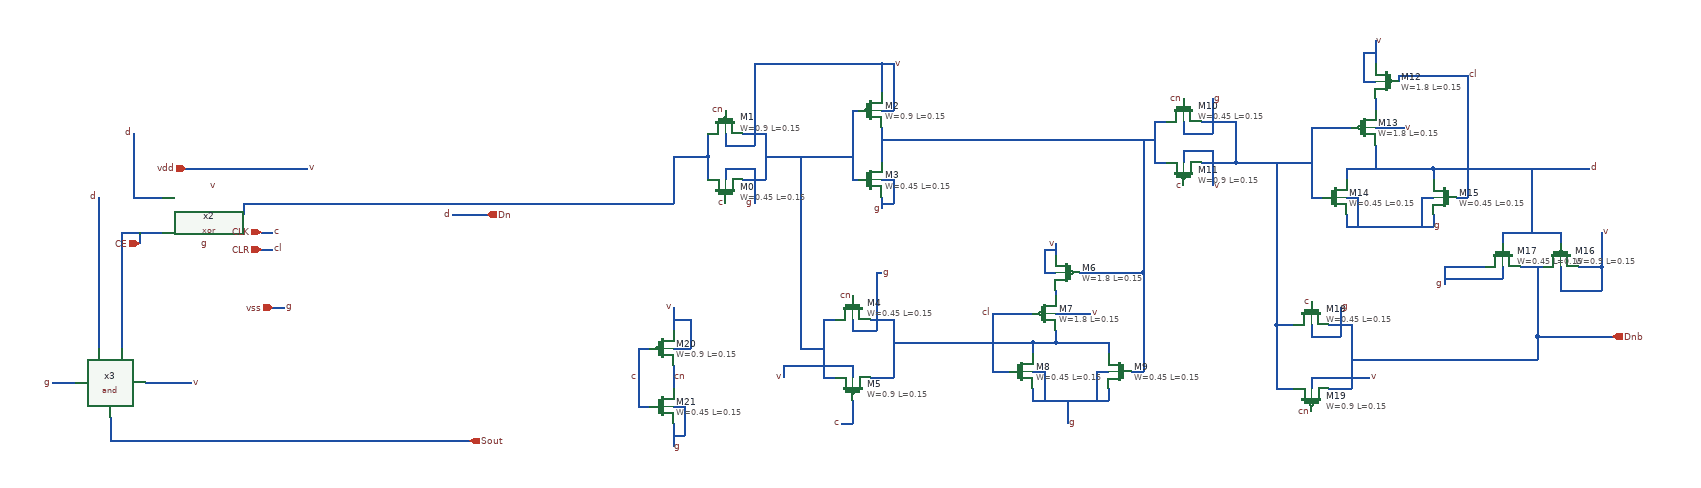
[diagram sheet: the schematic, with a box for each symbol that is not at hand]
v {xschem version=2.9.9 file_version=1.2 }
G {}
K {}
V {}
S {}
E {}
N 60 -30 60 230 { lab=d}
N 120 -30 170 -30 { lab=d}
N 120 -140 120 -30 { lab=d}
N 140 290 190 290 { lab=v}
N -20 290 20 290 { lab=g}
N 80 350 80 390 { lab=Sout}
N 80 390 700 390 { lab=Sout}
N 670 0 730 -0 { lab=d}
N 210 -80 230 -80 { lab=vdd}
N 360 160 380 160 { lab=g}
N 340 30 360 30 { lab=c}
N 340 60 360 60 { lab=cl}
N 130 30 130 50 { lab=CE}
N 240 -80 420 -80 { lab=v}
N 230 -80 240 -80 { lab=vdd}
N 190 290 220 290 { lab=v}
N 100 30 100 230 { lab=CE}
N 100 30 170 30 { lab=CE}
N 310 -20 310 -0 { lab=#net1}
N 310 -20 360 -20 { lab=#net1}
N 1050 -100 1110 -100 { lab=#net1}
N 1110 -140 1110 -100 { lab=#net1}
N 1110 -100 1110 -60 { lab=#net1}
N 1170 -140 1210 -140 { lab=#net2}
N 1170 -60 1210 -60 { lab=#net2}
N 1210 -140 1210 -60 { lab=#net2}
N 1210 -100 1290 -100 { lab=#net2}
N 1360 -60 1370 -60 { lab=#net2}
N 1360 -180 1360 -60 { lab=#net2}
N 1360 -180 1370 -180 { lab=#net2}
N 1410 -150 1410 -90 { lab=#net3}
N 1290 -100 1360 -100 { lab=#net2}
N 1140 -140 1140 -120 { lab=v}
N 1140 -120 1190 -120 { lab=v}
N 1190 -260 1190 -120 { lab=v}
N 1410 -260 1410 -210 { lab=v}
N 1190 -260 1410 -260 { lab=v}
N 1390 280 1410 280 { lab=#net4}
N 1390 180 1410 180 { lab=#net4}
N 1310 280 1330 280 { lab=#net2}
N 1310 180 1310 280 { lab=#net2}
N 1310 180 1330 180 { lab=#net2}
N 1270 230 1310 230 { lab=#net2}
N 1270 -100 1270 230 { lab=#net2}
N 1360 180 1360 200 { lab=g}
N 1360 200 1400 200 { lab=g}
N 1400 100 1400 200 { lab=g}
N 1400 100 1410 100 { lab=g}
N 1360 320 1360 360 { lab=c}
N 1340 360 1360 360 { lab=c}
N 1360 260 1360 280 { lab=v}
N 1240 260 1360 260 { lab=v}
N 1240 260 1240 280 { lab=v}
N 1140 -80 1140 -60 { lab=g}
N 1140 -80 1190 -80 { lab=g}
N 1190 -80 1190 -40 { lab=g}
N 1190 -40 1190 -20 { lab=g}
N 1410 280 1430 280 { lab=#net4}
N 1430 180 1430 280 { lab=#net4}
N 1410 180 1430 180 { lab=#net4}
N 1600 270 1630 270 { lab=cl}
N 1600 170 1600 270 { lab=cl}
N 1600 170 1670 170 { lab=cl}
N 1710 130 1710 140 { lab=#net5}
N 1710 200 1710 220 { lab=#net4}
N 1670 220 1710 220 { lab=#net4}
N 1670 220 1670 240 { lab=#net4}
N 1710 220 1800 220 { lab=#net4}
N 1800 220 1800 240 { lab=#net4}
N 1670 300 1670 320 { lab=g}
N 1670 320 1800 320 { lab=g}
N 1800 300 1800 320 { lab=g}
N 1730 320 1730 360 { lab=g}
N 1840 270 1860 270 { lab=#net3}
N 1860 100 1860 270 { lab=#net3}
N 1750 100 1860 100 { lab=#net3}
N 1710 50 1710 70 { lab=v}
N 1430 220 1670 220 { lab=#net4}
N 1670 270 1690 270 { lab=g}
N 1690 270 1690 320 { lab=g}
N 1780 270 1800 270 { lab=g}
N 1780 270 1780 320 { lab=g}
N 1710 170 1770 170 { lab=v}
N 1690 100 1710 100 { lab=v}
N 1690 60 1690 100 { lab=v}
N 1690 60 1710 60 { lab=v}
N 1410 -30 1410 -10 { lab=g}
N 1410 -20 1430 -20 { lab=g}
N 1430 -60 1430 -20 { lab=g}
N 1410 -60 1430 -60 { lab=g}
N 1410 -180 1430 -180 { lab=v}
N 1430 -260 1430 -180 { lab=v}
N 1410 -260 1430 -260 { lab=v}
N 1880 -160 1900 -160 { lab=#net3}
N 1880 -160 1880 -90 { lab=#net3}
N 1880 -90 1900 -90 { lab=#net3}
N 1410 -130 1880 -130 { lab=#net3}
N 1860 -130 1860 100 { lab=#net3}
N 1960 -90 2020 -90 { lab=#net6}
N 2020 -160 2020 -90 { lab=#net6}
N 1960 -160 2020 -160 { lab=#net6}
N 1930 -160 1930 -140 { lab=g}
N 1930 -140 1980 -140 { lab=g}
N 1980 -200 1980 -140 { lab=g}
N 1930 -110 1930 -90 { lab=v}
N 1930 -110 1980 -110 { lab=v}
N 1980 -110 1980 -50 { lab=v}
N 2210 -80 2210 -60 { lab=d}
N 2210 -80 2360 -80 { lab=d}
N 2360 -80 2360 -60 { lab=d}
N 2260 -120 2260 -80 { lab=d}
N 2260 -200 2260 -180 { lab=#net7}
N 2260 -300 2260 -260 { lab=v}
N 2210 0 2210 20 { lab=g}
N 2210 20 2360 20 { lab=g}
N 2360 0 2360 20 { lab=g}
N 2150 -30 2170 -30 { lab=#net6}
N 2150 -150 2150 -30 { lab=#net6}
N 2150 -150 2220 -150 { lab=#net6}
N 2400 -30 2420 -30 { lab=cl}
N 2420 -240 2420 -30 { lab=cl}
N 2300 -240 2420 -240 { lab=cl}
N 2300 -240 2300 -230 { lab=cl}
N 2020 -90 2150 -90 { lab=#net6}
N 2360 -80 2630 -80 { lab=d}
N 2240 -230 2260 -230 { lab=v}
N 2240 -280 2240 -230 { lab=v}
N 2240 -280 2260 -280 { lab=v}
N 2260 -150 2310 -150 { lab=v}
N 2210 -30 2230 -30 { lab=g}
N 2230 -20 2230 20 { lab=g}
N 2230 -30 2230 -20 { lab=g}
N 2340 -30 2360 -30 { lab=g}
N 2340 -30 2340 20 { lab=g}
N 2480 30 2480 50 { lab=d}
N 2480 30 2580 30 { lab=d}
N 2580 30 2580 50 { lab=d}
N 2530 -80 2530 30 { lab=d}
N 2380 90 2450 90 { lab=g}
N 2380 90 2380 120 { lab=g}
N 2610 90 2650 90 { lab=v}
N 2650 30 2650 90 { lab=v}
N 2510 90 2550 90 { lab=Dnb}
N 2540 90 2540 210 { lab=Dnb}
N 2540 210 2670 210 { lab=Dnb}
N 2580 90 2580 130 { lab=v}
N 2580 130 2650 130 { lab=v}
N 2650 90 2650 130 { lab=v}
N 2480 90 2480 110 { lab=g}
N 2380 110 2480 110 { lab=g}
N 2180 190 2220 190 { lab=Dnb}
N 2220 190 2220 300 { lab=Dnb}
N 2180 300 2220 300 { lab=Dnb}
N 2220 250 2540 250 { lab=Dnb}
N 2540 210 2540 250 { lab=Dnb}
N 2090 190 2120 190 { lab=#net6}
N 2090 190 2090 300 { lab=#net6}
N 2090 300 2120 300 { lab=#net6}
N 2090 -90 2090 190 { lab=#net6}
N 2150 190 2150 210 { lab=g}
N 2150 210 2200 210 { lab=g}
N 2200 160 2200 210 { lab=g}
N 2150 280 2150 300 { lab=v}
N 2150 280 2250 280 { lab=v}
N 1050 260 1050 300 { lab=cn}
N 990 330 1010 330 { lab=c}
N 990 230 990 330 { lab=c}
N 990 230 1010 230 { lab=c}
N 1050 160 1050 200 { lab=v}
N 1050 360 1050 400 { lab=g}
N 1050 330 1070 330 { lab=g}
N 1070 330 1070 380 { lab=g}
N 1050 380 1070 380 { lab=g}
N 1050 230 1080 230 { lab=v}
N 1080 180 1080 230 { lab=v}
N 1050 180 1080 180 { lab=v}
N 360 -20 1050 -20 { lab=#net1}
N 1050 -100 1050 -20 { lab=#net1}
C {xor/xor.sym} 180 0 0 0 {name=x2}
C {and/and.sym} 80 270 1 0 {name=x3}
C {opin.sym} 730 0 0 0 {name=p1 lab=Dn}
C {opin.sym} 700 390 0 0 {name=p2 lab=Sout}
C {ipin.sym} 210 -80 0 0 {name=p3 lab=vdd}
C {ipin.sym} 360 160 0 0 {name=p4 lab=vss}
C {ipin.sym} 340 30 0 0 {name=p5 lab=CLK}
C {ipin.sym} 340 60 0 0 {name=p6 lab=CLR}
C {ipin.sym} 130 50 3 0 {name=p7 lab=CE}
C {sky130_fd_pr/nfet_01v8.sym} 1140 -40 1 1 {name=M0
L=0.15
W=0.45
nf=1 
mult=1
ad="'int((nf+1)/2) * W/nf * 0.29'" 
pd="'2*int((nf+1)/2) * (W/nf + 0.29)'"
as="'int((nf+2)/2) * W/nf * 0.29'" 
ps="'2*int((nf+2)/2) * (W/nf + 0.29)'"
nrd="'0.29 / W'" nrs="'0.29 / W'"
sa=0 sb=0 sd=0
model=nfet_01v8
spiceprefix=X
}
C {sky130_fd_pr/pfet_01v8.sym} 1140 -160 1 0 {name=M1
L=0.15
W=0.9
nf=1
mult=1
ad="'int((nf+1)/2) * W/nf * 0.29'" 
pd="'2*int((nf+1)/2) * (W/nf + 0.29)'"
as="'int((nf+2)/2) * W/nf * 0.29'" 
ps="'2*int((nf+2)/2) * (W/nf + 0.29)'"
nrd="'0.29 / W'" nrs="'0.29 / W'"
sa=0 sb=0 sd=0
model=pfet_01v8
spiceprefix=X
}
C {sky130_fd_pr/pfet_01v8.sym} 1390 -180 0 0 {name=M2
L=0.15
W=0.9
nf=1
mult=1
ad="'int((nf+1)/2) * W/nf * 0.29'" 
pd="'2*int((nf+1)/2) * (W/nf + 0.29)'"
as="'int((nf+2)/2) * W/nf * 0.29'" 
ps="'2*int((nf+2)/2) * (W/nf + 0.29)'"
nrd="'0.29 / W'" nrs="'0.29 / W'"
sa=0 sb=0 sd=0
model=pfet_01v8
spiceprefix=X
}
C {sky130_fd_pr/nfet_01v8.sym} 1390 -60 0 0 {name=M3
L=0.15
W=0.45
nf=1 
mult=1
ad="'int((nf+1)/2) * W/nf * 0.29'" 
pd="'2*int((nf+1)/2) * (W/nf + 0.29)'"
as="'int((nf+2)/2) * W/nf * 0.29'" 
ps="'2*int((nf+2)/2) * (W/nf + 0.29)'"
nrd="'0.29 / W'" nrs="'0.29 / W'"
sa=0 sb=0 sd=0
model=nfet_01v8
spiceprefix=X
}
C {sky130_fd_pr/nfet_01v8.sym} 1360 160 3 1 {name=M4
L=0.15
W=0.45
nf=1 
mult=1
ad="'int((nf+1)/2) * W/nf * 0.29'" 
pd="'2*int((nf+1)/2) * (W/nf + 0.29)'"
as="'int((nf+2)/2) * W/nf * 0.29'" 
ps="'2*int((nf+2)/2) * (W/nf + 0.29)'"
nrd="'0.29 / W'" nrs="'0.29 / W'"
sa=0 sb=0 sd=0
model=nfet_01v8
spiceprefix=X
}
C {sky130_fd_pr/pfet_01v8.sym} 1360 300 3 0 {name=M5
L=0.15
W=0.9
nf=1
mult=1
ad="'int((nf+1)/2) * W/nf * 0.29'" 
pd="'2*int((nf+1)/2) * (W/nf + 0.29)'"
as="'int((nf+2)/2) * W/nf * 0.29'" 
ps="'2*int((nf+2)/2) * (W/nf + 0.29)'"
nrd="'0.29 / W'" nrs="'0.29 / W'"
sa=0 sb=0 sd=0
model=pfet_01v8
spiceprefix=X
}
C {sky130_fd_pr/pfet_01v8.sym} 1730 100 0 1 {name=M6
L=0.15
W=1.8
nf=1
mult=1
ad="'int((nf+1)/2) * W/nf * 0.29'" 
pd="'2*int((nf+1)/2) * (W/nf + 0.29)'"
as="'int((nf+2)/2) * W/nf * 0.29'" 
ps="'2*int((nf+2)/2) * (W/nf + 0.29)'"
nrd="'0.29 / W'" nrs="'0.29 / W'"
sa=0 sb=0 sd=0
model=pfet_01v8
spiceprefix=X
}
C {sky130_fd_pr/pfet_01v8.sym} 1690 170 0 0 {name=M7
L=0.15
W=1.8
nf=1
mult=1
ad="'int((nf+1)/2) * W/nf * 0.29'" 
pd="'2*int((nf+1)/2) * (W/nf + 0.29)'"
as="'int((nf+2)/2) * W/nf * 0.29'" 
ps="'2*int((nf+2)/2) * (W/nf + 0.29)'"
nrd="'0.29 / W'" nrs="'0.29 / W'"
sa=0 sb=0 sd=0
model=pfet_01v8
spiceprefix=X
}
C {sky130_fd_pr/nfet_01v8.sym} 1650 270 0 0 {name=M8
L=0.15
W=0.45
nf=1 
mult=1
ad="'int((nf+1)/2) * W/nf * 0.29'" 
pd="'2*int((nf+1)/2) * (W/nf + 0.29)'"
as="'int((nf+2)/2) * W/nf * 0.29'" 
ps="'2*int((nf+2)/2) * (W/nf + 0.29)'"
nrd="'0.29 / W'" nrs="'0.29 / W'"
sa=0 sb=0 sd=0
model=nfet_01v8
spiceprefix=X
}
C {sky130_fd_pr/nfet_01v8.sym} 1820 270 0 1 {name=M9
L=0.15
W=0.45
nf=1 
mult=1
ad="'int((nf+1)/2) * W/nf * 0.29'" 
pd="'2*int((nf+1)/2) * (W/nf + 0.29)'"
as="'int((nf+2)/2) * W/nf * 0.29'" 
ps="'2*int((nf+2)/2) * (W/nf + 0.29)'"
nrd="'0.29 / W'" nrs="'0.29 / W'"
sa=0 sb=0 sd=0
model=nfet_01v8
spiceprefix=X
}
C {sky130_fd_pr/nfet_01v8.sym} 1930 -180 1 0 {name=M10
L=0.15
W=0.45
nf=1 
mult=1
ad="'int((nf+1)/2) * W/nf * 0.29'" 
pd="'2*int((nf+1)/2) * (W/nf + 0.29)'"
as="'int((nf+2)/2) * W/nf * 0.29'" 
ps="'2*int((nf+2)/2) * (W/nf + 0.29)'"
nrd="'0.29 / W'" nrs="'0.29 / W'"
sa=0 sb=0 sd=0
model=nfet_01v8
spiceprefix=X
}
C {sky130_fd_pr/pfet_01v8.sym} 1930 -70 1 1 {name=M11
L=0.15
W=0.9
nf=1
mult=1
ad="'int((nf+1)/2) * W/nf * 0.29'" 
pd="'2*int((nf+1)/2) * (W/nf + 0.29)'"
as="'int((nf+2)/2) * W/nf * 0.29'" 
ps="'2*int((nf+2)/2) * (W/nf + 0.29)'"
nrd="'0.29 / W'" nrs="'0.29 / W'"
sa=0 sb=0 sd=0
model=pfet_01v8
spiceprefix=X
}
C {sky130_fd_pr/pfet_01v8.sym} 2280 -230 0 1 {name=M12
L=0.15
W=1.8
nf=1
mult=1
ad="'int((nf+1)/2) * W/nf * 0.29'" 
pd="'2*int((nf+1)/2) * (W/nf + 0.29)'"
as="'int((nf+2)/2) * W/nf * 0.29'" 
ps="'2*int((nf+2)/2) * (W/nf + 0.29)'"
nrd="'0.29 / W'" nrs="'0.29 / W'"
sa=0 sb=0 sd=0
model=pfet_01v8
spiceprefix=X
}
C {sky130_fd_pr/pfet_01v8.sym} 2240 -150 0 0 {name=M13
L=0.15
W=1.8
nf=1
mult=1
ad="'int((nf+1)/2) * W/nf * 0.29'" 
pd="'2*int((nf+1)/2) * (W/nf + 0.29)'"
as="'int((nf+2)/2) * W/nf * 0.29'" 
ps="'2*int((nf+2)/2) * (W/nf + 0.29)'"
nrd="'0.29 / W'" nrs="'0.29 / W'"
sa=0 sb=0 sd=0
model=pfet_01v8
spiceprefix=X
}
C {sky130_fd_pr/nfet_01v8.sym} 2190 -30 0 0 {name=M14
L=0.15
W=0.45
nf=1 
mult=1
ad="'int((nf+1)/2) * W/nf * 0.29'" 
pd="'2*int((nf+1)/2) * (W/nf + 0.29)'"
as="'int((nf+2)/2) * W/nf * 0.29'" 
ps="'2*int((nf+2)/2) * (W/nf + 0.29)'"
nrd="'0.29 / W'" nrs="'0.29 / W'"
sa=0 sb=0 sd=0
model=nfet_01v8
spiceprefix=X
}
C {sky130_fd_pr/nfet_01v8.sym} 2380 -30 0 1 {name=M15
L=0.15
W=0.45
nf=1 
mult=1
ad="'int((nf+1)/2) * W/nf * 0.29'" 
pd="'2*int((nf+1)/2) * (W/nf + 0.29)'"
as="'int((nf+2)/2) * W/nf * 0.29'" 
ps="'2*int((nf+2)/2) * (W/nf + 0.29)'"
nrd="'0.29 / W'" nrs="'0.29 / W'"
sa=0 sb=0 sd=0
model=nfet_01v8
spiceprefix=X
}
C {sky130_fd_pr/pfet_01v8.sym} 2580 70 1 0 {name=M16
L=0.15
W=0.9
nf=1
mult=1
ad="'int((nf+1)/2) * W/nf * 0.29'" 
pd="'2*int((nf+1)/2) * (W/nf + 0.29)'"
as="'int((nf+2)/2) * W/nf * 0.29'" 
ps="'2*int((nf+2)/2) * (W/nf + 0.29)'"
nrd="'0.29 / W'" nrs="'0.29 / W'"
sa=0 sb=0 sd=0
model=pfet_01v8
spiceprefix=X
}
C {sky130_fd_pr/nfet_01v8.sym} 2480 70 1 0 {name=M17
L=0.15
W=0.45
nf=1 
mult=1
ad="'int((nf+1)/2) * W/nf * 0.29'" 
pd="'2*int((nf+1)/2) * (W/nf + 0.29)'"
as="'int((nf+2)/2) * W/nf * 0.29'" 
ps="'2*int((nf+2)/2) * (W/nf + 0.29)'"
nrd="'0.29 / W'" nrs="'0.29 / W'"
sa=0 sb=0 sd=0
model=nfet_01v8
spiceprefix=X
}
C {sky130_fd_pr/nfet_01v8.sym} 2150 170 3 1 {name=M18
L=0.15
W=0.45
nf=1 
mult=1
ad="'int((nf+1)/2) * W/nf * 0.29'" 
pd="'2*int((nf+1)/2) * (W/nf + 0.29)'"
as="'int((nf+2)/2) * W/nf * 0.29'" 
ps="'2*int((nf+2)/2) * (W/nf + 0.29)'"
nrd="'0.29 / W'" nrs="'0.29 / W'"
sa=0 sb=0 sd=0
model=nfet_01v8
spiceprefix=X
}
C {sky130_fd_pr/pfet_01v8.sym} 2150 320 3 0 {name=M19
L=0.15
W=0.9
nf=1
mult=1
ad="'int((nf+1)/2) * W/nf * 0.29'" 
pd="'2*int((nf+1)/2) * (W/nf + 0.29)'"
as="'int((nf+2)/2) * W/nf * 0.29'" 
ps="'2*int((nf+2)/2) * (W/nf + 0.29)'"
nrd="'0.29 / W'" nrs="'0.29 / W'"
sa=0 sb=0 sd=0
model=pfet_01v8
spiceprefix=X
}
C {sky130_fd_pr/pfet_01v8.sym} 1030 230 0 0 {name=M20
L=0.15
W=0.9
nf=1
mult=1
ad="'int((nf+1)/2) * W/nf * 0.29'" 
pd="'2*int((nf+1)/2) * (W/nf + 0.29)'"
as="'int((nf+2)/2) * W/nf * 0.29'" 
ps="'2*int((nf+2)/2) * (W/nf + 0.29)'"
nrd="'0.29 / W'" nrs="'0.29 / W'"
sa=0 sb=0 sd=0
model=pfet_01v8
spiceprefix=X
}
C {sky130_fd_pr/nfet_01v8.sym} 1030 330 0 0 {name=M21
L=0.15
W=0.45
nf=1 
mult=1
ad="'int((nf+1)/2) * W/nf * 0.29'" 
pd="'2*int((nf+1)/2) * (W/nf + 0.29)'"
as="'int((nf+2)/2) * W/nf * 0.29'" 
ps="'2*int((nf+2)/2) * (W/nf + 0.29)'"
nrd="'0.29 / W'" nrs="'0.29 / W'"
sa=0 sb=0 sd=0
model=nfet_01v8
spiceprefix=X
}
C {lab_pin.sym} 1140 -180 0 0 {name=l1 sig_type=std_logic lab=cn}
C {lab_pin.sym} 1140 -20 0 0 {name=l2 sig_type=std_logic lab=c}
C {lab_pin.sym} 1190 -20 3 0 {name=l3 sig_type=std_logic lab=g}
C {lab_pin.sym} 1410 100 2 0 {name=l4 sig_type=std_logic lab=g}
C {lab_pin.sym} 1360 140 1 0 {name=l5 sig_type=std_logic lab=cn}
C {lab_pin.sym} 1340 360 0 0 {name=l6 sig_type=std_logic lab=c}
C {lab_pin.sym} 1240 280 0 0 {name=l7 sig_type=std_logic lab=v}
C {lab_pin.sym} 420 -80 2 0 {name=l8 sig_type=std_logic lab=v}
C {lab_pin.sym} 1730 360 2 0 {name=l9 sig_type=std_logic lab=g}
C {lab_pin.sym} 1710 50 0 0 {name=l10 sig_type=std_logic lab=v}
C {lab_pin.sym} 1600 170 0 0 {name=l11 sig_type=std_logic lab=cl}
C {lab_pin.sym} 1770 170 2 0 {name=l12 sig_type=std_logic lab=v}
C {lab_pin.sym} 1410 -10 0 0 {name=l13 sig_type=std_logic lab=g}
C {lab_pin.sym} 1980 -50 2 0 {name=l14 sig_type=std_logic lab=v}
C {lab_pin.sym} 1980 -200 2 0 {name=l15 sig_type=std_logic lab=g}
C {lab_pin.sym} 1930 -200 0 0 {name=l16 sig_type=std_logic lab=cn}
C {lab_pin.sym} 1930 -50 0 0 {name=l17 sig_type=std_logic lab=c}
C {lab_pin.sym} 2260 -300 2 0 {name=l18 sig_type=std_logic lab=v}
C {lab_pin.sym} 2360 20 2 0 {name=l19 sig_type=std_logic lab=g}
C {lab_pin.sym} 2420 -240 2 0 {name=l20 sig_type=std_logic lab=cl}
C {lab_pin.sym} 2310 -150 2 0 {name=l21 sig_type=std_logic lab=v}
C {lab_pin.sym} 2380 120 3 0 {name=l22 sig_type=std_logic lab=g}
C {lab_pin.sym} 2650 30 2 0 {name=l23 sig_type=std_logic lab=v}
C {lab_pin.sym} 2150 150 1 0 {name=l24 sig_type=std_logic lab=c}
C {lab_pin.sym} 2150 340 3 0 {name=l25 sig_type=std_logic lab=cn}
C {lab_pin.sym} 2200 160 2 0 {name=l26 sig_type=std_logic lab=g}
C {lab_pin.sym} 2250 280 2 0 {name=l27 sig_type=std_logic lab=v}
C {lab_pin.sym} 990 280 0 0 {name=l28 sig_type=std_logic lab=c}
C {lab_pin.sym} 1050 280 2 0 {name=l29 sig_type=std_logic lab=cn}
C {lab_pin.sym} 1050 160 0 0 {name=l30 sig_type=std_logic lab=v}
C {lab_pin.sym} 1050 400 2 0 {name=l31 sig_type=std_logic lab=g}
C {lab_pin.sym} 360 30 2 0 {name=l32 sig_type=std_logic lab=c}
C {lab_pin.sym} 360 60 2 0 {name=l33 sig_type=std_logic lab=cl}
C {lab_pin.sym} 1430 -260 2 0 {name=l35 sig_type=std_logic lab=v}
C {opin.sym} 2670 210 0 0 {name=p8 lab=Dnb}
C {lab_pin.sym} 2630 -80 2 0 {name=l36 sig_type=std_logic lab=d}
C {lab_pin.sym} 380 160 2 0 {name=l38 sig_type=std_logic lab=g}
C {lab_pin.sym} 220 290 2 0 {name=l34 sig_type=std_logic lab=v}
C {lab_pin.sym} 250 -50 2 0 {name=l39 sig_type=std_logic lab=v}
C {lab_pin.sym} -20 290 0 0 {name=l40 sig_type=std_logic lab=g}
C {lab_pin.sym} 250 50 0 0 {name=l41 sig_type=std_logic lab=g}
C {lab_pin.sym} 670 0 0 0 {name=l42 sig_type=std_logic lab=d}
C {lab_pin.sym} 120 -140 0 0 {name=l37 sig_type=std_logic lab=d}
C {lab_pin.sym} 60 -30 0 0 {name=l43 sig_type=std_logic lab=d}
